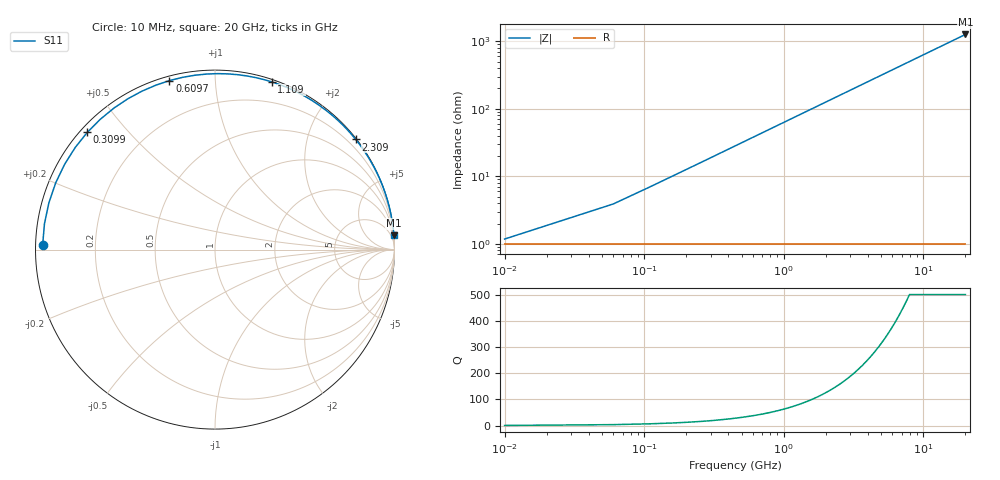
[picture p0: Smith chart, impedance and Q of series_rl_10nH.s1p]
! Created with skrf 2.1.0 (http://scikit-rf.org).
# GHz S RI R 50.0
!freq ReS11 ImS11
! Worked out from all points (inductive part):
!   401 points, 10 MHz to 20 GHz, reference 50 ohm
!   read as one part to ground: L = 10 nH near 110 MHz
!   highest Q = 1.26e+03 at 20 GHz (marker M1), where L = 10 nH
!   S11 on the Smith chart (normalised r, x): 10 MHz: 0.02, +0.01; 309.9 MHz: 0.02, +0.39; 609.7 MHz: 0.02, +0.77; 1.109 GHz: 0.02, +1.39; 2.309 GHz: 0.02, +2.90; 20 GHz: 0, +25
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0.01  -0.9605 0.0242
0.059975  -0.9501 0.1441
0.10995  -0.9255 0.2608
0.159925  -0.8875 0.3719
0.259875  -0.7785 0.5694
0.30985  -0.7114 0.6533
0.359825  -0.6387 0.7265
0.459775  -0.4845 0.8409
0.6097  -0.2535 0.9416
0.70965  -0.1113 0.9716
0.859575  0.0757 0.9788
0.959525  0.1821 0.9668
1.10945  0.3164 0.9344
1.359325  0.4846 0.8631
1.6092  0.6023 0.7884
1.90905  0.6998 0.706
2.30885  0.7843 0.6135
2.50875  0.8142 0.5743
3.0085  0.867 0.4931
3.6082  0.9056 0.4198
5.0075  0.9498 0.3097
6.156925  0.9665 0.2541
7.50625  0.9773 0.2096
10.005  0.9872 0.158
12.50375  0.9918 0.1268
15.0025  0.9943 0.1058
17.50125  0.9958 0.0907
20  0.9968 0.0794
